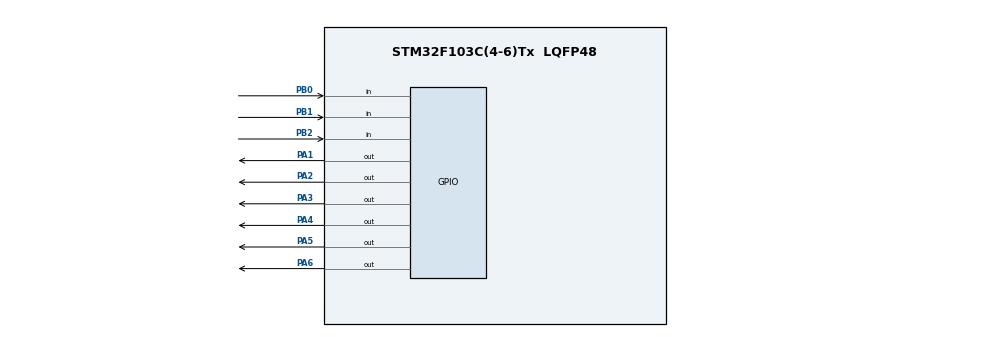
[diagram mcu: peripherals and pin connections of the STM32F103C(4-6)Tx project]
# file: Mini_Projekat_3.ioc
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Mcu.Family=STM32F1
Mcu.Name=STM32F103C(4-6)Tx
Mcu.Package=LQFP48
NVIC.PriorityGroup=NVIC_PRIORITYGROUP_4
PA1.Signal=GPIO_Output
PA2.Signal=GPIO_Output
PA3.Signal=GPIO_Output
PA4.Signal=GPIO_Output
PA5.Signal=GPIO_Output
PA6.Signal=GPIO_Output
PB0.Signal=GPIO_Input
PB1.Signal=GPIO_Input
PB2.Signal=GPIO_Input
ProjectManager.HeapSize=0x200
ProjectManager.StackSize=0x400
ProjectManager.TargetToolchain=STM32CubeIDE
RCC.APB1Freq_Value=8000000
RCC.APB2Freq_Value=8000000
board=custom

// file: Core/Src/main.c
/* USER CODE BEGIN Header */
/**
  ******************************************************************************
  * @file           : main.c
  * @brief          : Main program body
  ******************************************************************************
  * @attention
  *
  * Copyright (c) 2022 STMicroelectronics.
  * All rights reserved.
  *
  * This software is licensed under terms that can be found in the LICENSE file
  * in the root directory of this software component.
  * If no LICENSE file comes with this software, it is provided AS-IS.
  *
  ******************************************************************************
  */
/* USER CODE END Header */
#include "main.h"

#define out_1 GPIO_PIN_1
#define out_2 GPIO_PIN_2
#define out_3 GPIO_PIN_3
#define out_4 GPIO_PIN_4

#define in_1 GPIO_PIN_0
#define in_2 GPIO_PIN_1
#define in_3 GPIO_PIN_15

int OUTS[] = {out_1,out_2,out_3,out_4};

#define MAX_OUTS 4
#define MAX_INS 3

void SystemClock_Config(void);
static void MX_GPIO_Init(void);

int main(void)
{

  /* MCU Configuration--------------------------------------------------------*/

  /* Reset of all peripherals, Initializes the Flash interface and the Systick. */
  HAL_Init();

  /* Configure the system clock */
  SystemClock_Config();

  /* Initialize all configured peripherals */
  MX_GPIO_Init();

  /* Infinite loop */

  int i,j,flag = 1,var;

  int key[] = {8,3}; // sifra za ulaz
  int key_length = 2;
  int try[2]; // pokusana sifra
  int counter = 0,br = 1; // pomocne promenljive

  int matrica[MAX_OUTS][MAX_INS]; // matrica brojeva od 0 do 9, tacnije od 1 do 0

  for(i = 0; i< MAX_OUTS; i++)
	  for(j = 0; j < MAX_INS; j++)
		  if(i != 3 || j != 1)
			  matrica[i][j] = br++;
		  else
			  matrica[i][j] = 0;

  /* matrica[i][j]
   *
   * 1  2  3
   * 4  5  6
   * 7  8  9
   * 10 0  11
   *
   */
   // 10 i 11 simuliraju * i #, zbog int tipa

  while (1) // sifra je 83, vertikale 2 i 3 rade
  {
	  HAL_GPIO_WritePin(GPIOA, GPIO_PIN_5, GPIO_PIN_SET); // dioda ne svetli
	  HAL_GPIO_WritePin(GPIOA, GPIO_PIN_6, GPIO_PIN_SET); // dioda ne svetli

	  while(counter < key_length)
	  {
		  for(i = 0; i < MAX_OUTS; i++)
		  {
			  HAL_GPIO_WritePin(GPIOA, OUTS[i], GPIO_PIN_SET);

			  if(HAL_GPIO_ReadPin(GPIOA, in_3))
			  {
				  try[counter++] = matrica[i][0];
			  }
			  if(HAL_GPIO_ReadPin(GPIOB, GPIO_PIN_0))
			  {
				  try[counter++] = matrica[i][1];
			  }
			  if(HAL_GPIO_ReadPin(GPIOA, in_1))
			  {
				  try[counter++] = matrica[i][2];
			  }

			  HAL_Delay(30);
			  HAL_GPIO_WritePin(GPIOA, OUTS[i], GPIO_PIN_RESET);
		  }
	  }

	  //Provera sifre
	  for (var = 0; var < key_length; var++)
		if(key[var] != try[var])
			flag = 0;

	  if(flag == 1)
		  HAL_GPIO_WritePin(GPIOA,  GPIO_PIN_5, GPIO_PIN_RESET);
	  else
		  HAL_GPIO_WritePin(GPIOA, GPIO_PIN_6, GPIO_PIN_RESET);

	  //restartujemo flag i brojac
	  flag = 1;
	  counter = 0;
	  HAL_Delay(2000); // vrata su otvorena 2 sekunde
  }

}

void SystemClock_Config(void)
{
  RCC_OscInitTypeDef RCC_OscInitStruct = {0};
  RCC_ClkInitTypeDef RCC_ClkInitStruct = {0};

  /** Initializes the RCC Oscillators according to the specified parameters
  * in the RCC_OscInitTypeDef structure.
  */
  RCC_OscInitStruct.OscillatorType = RCC_OSCILLATORTYPE_HSI;
  RCC_OscInitStruct.HSIState = RCC_HSI_ON;
  RCC_OscInitStruct.HSICalibrationValue = RCC_HSICALIBRATION_DEFAULT;
  RCC_OscInitStruct.PLL.PLLState = RCC_PLL_NONE;
  if (HAL_RCC_OscConfig(&RCC_OscInitStruct) != HAL_OK)
  {
    Error_Handler();
  }

  /** Initializes the CPU, AHB and APB buses clocks
  */
  RCC_ClkInitStruct.ClockType = RCC_CLOCKTYPE_HCLK|RCC_CLOCKTYPE_SYSCLK
                              |RCC_CLOCKTYPE_PCLK1|RCC_CLOCKTYPE_PCLK2;
  RCC_ClkInitStruct.SYSCLKSource = RCC_SYSCLKSOURCE_HSI;
  RCC_ClkInitStruct.AHBCLKDivider = RCC_SYSCLK_DIV1;
  RCC_ClkInitStruct.APB1CLKDivider = RCC_HCLK_DIV1;
  RCC_ClkInitStruct.APB2CLKDivider = RCC_HCLK_DIV1;

  if (HAL_RCC_ClockConfig(&RCC_ClkInitStruct, FLASH_LATENCY_0) != HAL_OK)
  {
    Error_Handler();
  }
}

static void MX_GPIO_Init(void)
{
  GPIO_InitTypeDef GPIO_InitStruct = {0};

  /* GPIO Ports Clock Enable */
  __HAL_RCC_GPIOA_CLK_ENABLE();
  __HAL_RCC_GPIOB_CLK_ENABLE();

  /*Configure GPIO pin Output Level */
  HAL_GPIO_WritePin(GPIOA, GPIO_PIN_1|GPIO_PIN_2|GPIO_PIN_3|GPIO_PIN_4
                          |GPIO_PIN_5|GPIO_PIN_6, GPIO_PIN_RESET);

  /*Configure GPIO pins : PA1 PA2 PA3 PA4
                           PA5 PA6 */
  GPIO_InitStruct.Pin = GPIO_PIN_1|GPIO_PIN_2|GPIO_PIN_3|GPIO_PIN_4
                          |GPIO_PIN_5|GPIO_PIN_6;
  GPIO_InitStruct.Mode = GPIO_MODE_OUTPUT_PP;
  GPIO_InitStruct.Pull = GPIO_NOPULL;
  GPIO_InitStruct.Speed = GPIO_SPEED_FREQ_LOW;
  HAL_GPIO_Init(GPIOA, &GPIO_InitStruct);

  /*Configure GPIO pins : PB0 PB1 PB2 */
  GPIO_InitStruct.Pin = GPIO_PIN_0|GPIO_PIN_14|GPIO_PIN_15;
  GPIO_InitStruct.Mode = GPIO_MODE_INPUT;
  GPIO_InitStruct.Pull = GPIO_NOPULL;
  HAL_GPIO_Init(GPIOB, &GPIO_InitStruct);

  	GPIO_InitStruct.Pin = GPIO_PIN_0|GPIO_PIN_8|GPIO_PIN_9|GPIO_PIN_10|GPIO_PIN_11|GPIO_PIN_12|GPIO_PIN_13|GPIO_PIN_14|GPIO_PIN_15;
    GPIO_InitStruct.Mode = GPIO_MODE_INPUT;
    GPIO_InitStruct.Pull = GPIO_NOPULL;
    HAL_GPIO_Init(GPIOA, &GPIO_InitStruct);

}

void Error_Handler(void)
{
  __disable_irq();
  while (1)
  {
  }
}
